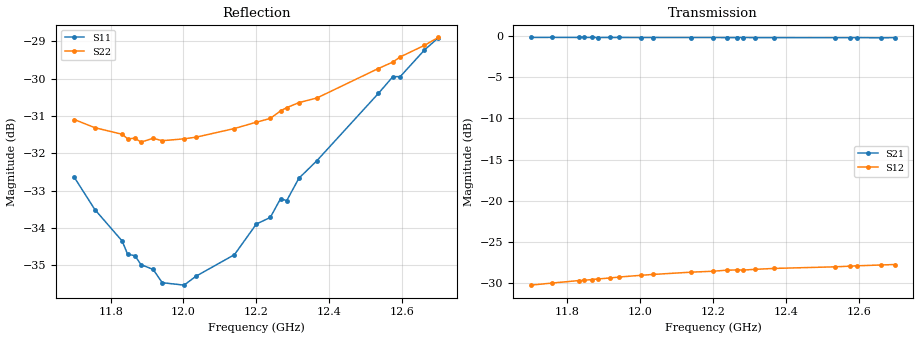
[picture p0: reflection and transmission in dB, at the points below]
! MS46524B
! 12345/M1: Not Set/M2: Not Set
! 3/11/2021 9:19:46 PM
! D:\WEBSITE FILES\DATASHEETS\MEASURED DATA\11.7 - 12.7 GHZ (D4I1213).S2P
! CHANNEL.1
! TR.MEASUREMENT
! RAW.DATA
# GHZ S RI R 50.0
! FREQ.GHZ  S11RE  S11IM  S21RE  S21IM  S12RE  S12IM  S22RE  S22IM
!; PortSelection: Port_12
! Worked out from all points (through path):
!   601 points, 11.7 GHz to 12.7 GHz, reference 50 ohm
!   highest |S21| = -0.15 dB at 11.76 GHz (marker M1); lowest = -0.2 dB at 12.66 GHz (marker M2)
!   lowest |S11| = -35.5 dB at 12 GHz (marker M3), VSWR 1.03, Z = 50.2 + j1.66 ohm
!   |S11| at or under -10 dB: start of sweep to end of sweep
!   |S22| runs from -31.7 to -28.9 dB; largest |S21 - S12| = 0.98
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11.7  0.0166 0.0164  0.9494 0.2511  0.0229 -0.0204  0.0133 -0.0245
11.75667  0.0139 0.0159  0.9655 0.186  0.0219 -0.0227  0.00994 -0.0253
11.83167  0.0107 0.0159  0.9768 0.1009  0.0202 -0.0257  0.00531 -0.0261
11.84667  0.00943 0.0158  0.979 0.0829  0.0198 -0.0262  0.00439 -0.0259
11.86667  0.00892 0.016  0.981 0.0591  0.0192 -0.027  0.00333 -0.0261
11.88333  0.00785 0.016  0.9805 0.0394  0.0187 -0.0277  0.00229 -0.0259
11.91667  0.00677 0.0162  0.9817 0.00122  0.0175 -0.029  0.000538 -0.0263
11.94167  0.0053 0.016  0.9818 -0.0272  0.0167 -0.03  -0.000792 -0.0261
12.00167  0.00276 0.0165  0.9757 -0.0976  0.0144 -0.0321  -0.00437 -0.0259
12.035  0.00187 0.0171  0.972 -0.1362  0.0126 -0.0333  -0.00604 -0.0257
12.14  -0.00255 0.0182  0.947 -0.2566  0.00698 -0.0361  -0.0114 -0.0246
12.2  -0.00486 0.0196  0.9263 -0.3238  0.00332 -0.0371  -0.0144 -0.0236
12.23833  -0.00606 0.0197  0.9099 -0.365  0.000804 -0.0378  -0.0162 -0.0228
12.26667  -0.00727 0.0206  0.8979 -0.3945  -0.00118 -0.0379  -0.0177 -0.0225
12.28333  -0.00712 0.0205  0.8901 -0.4127  -0.00222 -0.0378  -0.0184 -0.0223
12.31667  -0.00885 0.0215  0.8718 -0.448  -0.00446 -0.038  -0.02 -0.0215
12.36667  -0.0103 0.0223  0.844 -0.4972  -0.008 -0.0379  -0.0219 -0.0202
12.535  -0.0145 0.0265  0.7267 -0.6554  -0.02 -0.0342  -0.0282 -0.0164
12.575  -0.016 0.0275  0.6963 -0.6878  -0.023 -0.0327  -0.0294 -0.0156
12.595  -0.016 0.0275  0.6807 -0.7047  -0.0243 -0.032  -0.0303 -0.015
12.66167  -0.0173 0.0299  0.6202 -0.7553  -0.0287 -0.0288  -0.0325 -0.0131
12.7  -0.0184 0.0308  0.5877 -0.7838  -0.0311 -0.0266  -0.0337 -0.0124
